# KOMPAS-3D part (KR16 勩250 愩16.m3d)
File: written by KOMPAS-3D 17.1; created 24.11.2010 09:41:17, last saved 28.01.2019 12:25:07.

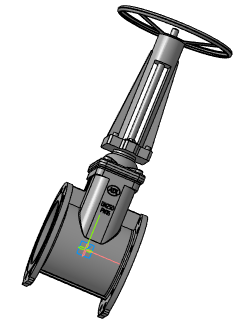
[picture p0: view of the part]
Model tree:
1. Плоскость XY
2. Плоскость ZX
3. Плоскость ZY
4. Ось X
5. Ось Y
6. Ось Z
7. Начало координат
8. Операция без истории:2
